# Generated directly from GDS by OpenFinRAM (gdstk)
VERSION 5.8 ;
BUSBITCHARS "[]" ;
DIVIDERCHAR "/" ;

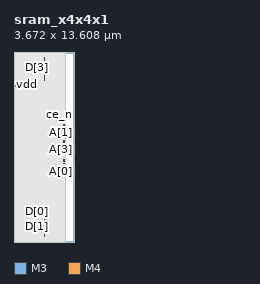
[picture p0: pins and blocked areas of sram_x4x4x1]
MACRO sram_x4x4x1
  CLASS BLOCK ;
  ORIGIN 0 0 ;
  FOREIGN sram_x4x4x1 0.054000 0.000000 ;
  SIZE 3.672000 BY 13.608000 ;
  SYMMETRY X Y ;
  PIN vdd
    DIRECTION INOUT ;
    USE POWER ;
    PORT
      LAYER M3 ;
        RECT 0.117000 11.151500 0.135000 11.421500 ;
    END
  END vdd
  PIN vss
    DIRECTION INOUT ;
    USE GROUND ;
    PORT
      LAYER M3 ;
        RECT 0.153000 11.151500 0.171000 11.501500 ;
    END
  END vss
  PIN clk
    DIRECTION INPUT ;
    USE SIGNAL ;
    PORT
      LAYER M4 ;
        RECT 3.534000 8.376000 3.618000 8.400000 ;
    END
  END clk
  PIN ce_n
    DIRECTION INPUT ;
    USE SIGNAL ;
    PORT
      LAYER M4 ;
        RECT 3.534000 8.568000 3.618000 8.592000 ;
    END
  END ce_n
  PIN oe_n
    DIRECTION INPUT ;
    USE SIGNAL ;
    PORT
      LAYER M4 ;
        RECT 3.534000 7.224000 3.618000 7.248000 ;
    END
  END oe_n
  PIN we_n
    DIRECTION INPUT ;
    USE SIGNAL ;
    PORT
      LAYER M4 ;
        RECT 3.534000 5.592000 3.618000 5.616000 ;
    END
  END we_n
  PIN sdel[0]
    DIRECTION INPUT ;
    USE SIGNAL ;
    PORT
      LAYER M4 ;
        RECT 3.534000 5.880000 3.618000 5.904000 ;
    END
  END sdel[0]
  PIN sdel[1]
    DIRECTION INPUT ;
    USE SIGNAL ;
    PORT
      LAYER M4 ;
        RECT 3.534000 7.128000 3.618000 7.152000 ;
    END
  END sdel[1]
  PIN sdel[2]
    DIRECTION INPUT ;
    USE SIGNAL ;
    PORT
      LAYER M4 ;
        RECT 3.534000 5.784000 3.618000 5.808000 ;
    END
  END sdel[2]
  PIN sdel[3]
    DIRECTION INPUT ;
    USE SIGNAL ;
    PORT
      LAYER M4 ;
        RECT 3.534000 8.664000 3.618000 8.688000 ;
    END
  END sdel[3]
  PIN A[0]
    DIRECTION INPUT ;
    USE SIGNAL ;
    PORT
      LAYER M4 ;
        RECT 3.534000 5.016000 3.618000 5.040000 ;
    END
  END A[0]
  PIN A[1]
    DIRECTION INPUT ;
    USE SIGNAL ;
    PORT
      LAYER M4 ;
        RECT 3.534000 7.800000 3.618000 7.824000 ;
    END
  END A[1]
  PIN A[2]
    DIRECTION INPUT ;
    USE SIGNAL ;
    PORT
      LAYER M4 ;
        RECT 3.534000 7.896000 3.618000 7.920000 ;
    END
  END A[2]
  PIN A[3]
    DIRECTION INPUT ;
    USE SIGNAL ;
    PORT
      LAYER M4 ;
        RECT 3.534000 6.648000 3.618000 6.672000 ;
    END
  END A[3]
  PIN D[0]
    DIRECTION INPUT ;
    USE SIGNAL ;
    PORT
      LAYER M3 ;
        RECT 1.611000 1.998000 1.629000 2.403000 ;
    END
  END D[0]
  PIN D[1]
    DIRECTION INPUT ;
    USE SIGNAL ;
    PORT
      LAYER M3 ;
        RECT 1.611000 0.918000 1.629000 1.323000 ;
    END
  END D[1]
  PIN D[2]
    DIRECTION INPUT ;
    USE SIGNAL ;
    PORT
      LAYER M3 ;
        RECT 1.611000 11.205000 1.629000 11.610000 ;
    END
  END D[2]
  PIN D[3]
    DIRECTION INPUT ;
    USE SIGNAL ;
    PORT
      LAYER M3 ;
        RECT 1.611000 12.285000 1.629000 12.690000 ;
    END
  END D[3]
  PIN Q[0]
    DIRECTION OUTPUT ;
    USE SIGNAL ;
    PORT
      LAYER M3 ;
        RECT 2.194000 1.444000 2.212000 2.062000 ;
    END
  END Q[0]
  PIN Q[1]
    DIRECTION OUTPUT ;
    USE SIGNAL ;
    PORT
      LAYER M3 ;
        RECT 2.194000 0.364000 2.212000 0.982000 ;
    END
  END Q[1]
  PIN Q[2]
    DIRECTION OUTPUT ;
    USE SIGNAL ;
    PORT
      LAYER M3 ;
        RECT 2.194000 11.546000 2.212000 12.164000 ;
    END
  END Q[2]
  PIN Q[3]
    DIRECTION OUTPUT ;
    USE SIGNAL ;
    PORT
      LAYER M3 ;
        RECT 2.194000 12.626000 2.212000 13.244000 ;
    END
  END Q[3]
  OBS
    LAYER M1 ;
      RECT 0 0 3.672000 13.608000 ;
    LAYER M2 ;
      RECT 0 0 3.672000 13.608000 ;
    LAYER M3 ;
      RECT 0 0 3.672000 13.608000 ;
    LAYER M4 ;
      RECT 0 0 3.672000 13.608000 ;
    LAYER M5 ;
      RECT 0 0 3.672000 13.608000 ;
  END
END sram_x4x4x1

END LIBRARY
